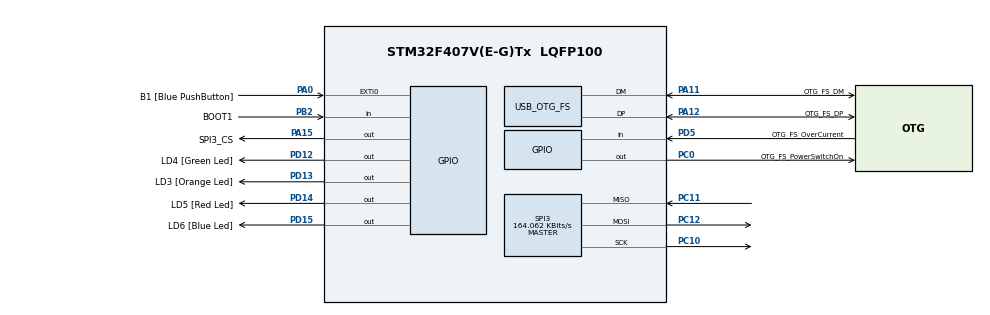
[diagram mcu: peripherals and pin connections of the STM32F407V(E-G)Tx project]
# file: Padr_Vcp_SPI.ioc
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FREERTOS.Tasks01=defaultTask,0,128,StartDefaultTask
Mcu.Family=STM32F4
Mcu.Name=STM32F407V(E-G)Tx
Mcu.Package=LQFP100
NVIC.OTG_FS_IRQn=true\:5\:0\:false
NVIC.PriorityGroup=NVIC_PRIORITYGROUP_4
PA0-WKUP.GPIO_Label=B1 [Blue PushButton]
PA0-WKUP.GPIO_ModeDefaultEXTI=GPIO_MODE_EVT_RISING
PA0-WKUP.GPIO_PuPd=GPIO_NOPULL
PA0-WKUP.Signal=GPXTI0
PA10.GPIO_Label=OTG_FS_ID
PA10.GPIO_Mode=GPIO_MODE_AF_PP
PA10.GPIO_PuPd=GPIO_NOPULL
PA10.GPIO_Speed=GPIO_SPEED_LOW
PA10.Signal=USB_OTG_FS_ID
PA11.GPIO_Label=OTG_FS_DM
PA11.GPIO_Mode=GPIO_MODE_AF_PP
PA11.GPIO_PuPd=GPIO_NOPULL
PA11.GPIO_Speed=GPIO_SPEED_LOW
PA11.Mode=Device_Only
PA11.Signal=USB_OTG_FS_DM
PA12.GPIO_Label=OTG_FS_DP
PA12.GPIO_Mode=GPIO_MODE_AF_PP
PA12.GPIO_PuPd=GPIO_NOPULL
PA12.GPIO_Speed=GPIO_SPEED_LOW
PA12.Mode=Device_Only
PA12.Signal=USB_OTG_FS_DP
PA13.GPIO_Label=SWDIO
PA13.Mode=Trace-Asynchronous_SW
PA13.Signal=SYS_JTMS-SWDIO
PA14.GPIO_Label=SWCLK
PA14.Mode=Trace-Asynchronous_SW
PA14.Signal=SYS_JTCK-SWCLK
PA15.GPIO_Label=SPI3_CS
PA15.Signal=GPIO_Output
PA9.GPIO_Label=VBUS_FS
PA9.GPIO_Mode=GPIO_MODE_INPUT
PA9.GPIO_PuPd=GPIO_NOPULL
PA9.Signal=USB_OTG_FS_VBUS
PB2.GPIO_Label=BOOT1
PB2.GPIO_Mode=GPIO_MODE_INPUT
PB2.GPIO_PuPd=GPIO_NOPULL
PB2.Signal=GPIO_Input
PB3.GPIO_Label=SWO
PB3.Mode=Trace-Asynchronous_SW
PB3.Signal=SYS_JTDO-SWO
PC0.GPIO_Label=OTG_FS_PowerSwitchOn
PC0.GPIO_PuPd=GPIO_NOPULL
PC0.GPIO_Speed=GPIO_SPEED_LOW
PC0.Signal=GPIO_Output
PC10.GPIO_Speed=GPIO_SPEED_LOW
PC10.Mode=Full_Duplex_Master
PC10.Signal=SPI3_SCK
PC11.GPIO_Speed=GPIO_SPEED_LOW
PC11.Mode=Full_Duplex_Master
PC11.Signal=SPI3_MISO
PC12.GPIO_Speed=GPIO_SPEED_LOW
PC12.Mode=Full_Duplex_Master
PC12.Signal=SPI3_MOSI
PD12.GPIO_Label=LD4 [Green Led]
PD12.GPIO_PuPd=GPIO_NOPULL
PD12.GPIO_Speed=GPIO_SPEED_LOW
PD12.Signal=GPIO_Output
PD13.GPIO_Label=LD3 [Orange Led]
PD13.GPIO_PuPd=GPIO_NOPULL
PD13.GPIO_Speed=GPIO_SPEED_LOW
PD13.Signal=GPIO_Output
PD14.GPIO_Label=LD5 [Red Led]
PD14.GPIO_PuPd=GPIO_NOPULL
PD14.GPIO_Speed=GPIO_SPEED_LOW
PD14.Signal=GPIO_Output
PD15.GPIO_Label=LD6 [Blue Led]
PD15.GPIO_PuPd=GPIO_NOPULL
PD15.GPIO_Speed=GPIO_SPEED_LOW
PD15.Signal=GPIO_Output
PD5.GPIO_Label=OTG_FS_OverCurrent
PD5.GPIO_Mode=GPIO_MODE_INPUT
PD5.GPIO_PuPd=GPIO_NOPULL
PD5.Signal=GPIO_Input
PH0-OSC_IN.GPIO_Label=PH0-OSC_IN
PH0-OSC_IN.Mode=HSE-External-Oscillator
PH0-OSC_IN.Signal=RCC_OSC_IN
PH1-OSC_OUT.GPIO_Label=PH1-OSC_OUT
PH1-OSC_OUT.Mode=HSE-External-Oscillator
PH1-OSC_OUT.Signal=RCC_OSC_OUT
ProjectManager.TargetToolchain=SW4STM32
RCC.AHBFreq_Value=168000000
RCC.APB1CLKDivider=RCC_HCLK_DIV4
RCC.APB1Freq_Value=42000000
RCC.APB1TimFreq_Value=84000000
RCC.APB2CLKDivider=RCC_HCLK_DIV2
RCC.APB2Freq_Value=84000000
RCC.APB2TimFreq_Value=168000000
RCC.CortexFreq_Value=168000000
RCC.HCLKFreq_Value=168000000
RCC.HSE_VALUE=8000000
RCC.HSI_VALUE=16000000
RCC.LSE_VALUE=32768
RCC.PLLM=8
RCC.PLLN=336
RCC.PLLQ=7
RCC.SYSCLKFreq_VALUE=168000000
RCC.SYSCLKSource=RCC_SYSCLKSOURCE_PLLCLK
RCC.VCOOutputFreq_Value=336000000
SPI3.BaudRatePrescaler=SPI_BAUDRATEPRESCALER_256
SPI3.CalculateBaudRate=164.062 KBits/s
SPI3.Mode=SPI_MODE_MASTER
USB_DEVICE.CLASS_NAME-CDC_FS=CDC
USB_DEVICE.USBD_HandleTypeDef-CDC_FS=hUsbDeviceFS
USB_DEVICE.USBD_SELF_POWERED-CDC_FS=0
USB_DEVICE.VirtualMode-CDC_FS=Cdc
USB_DEVICE.VirtualModeFS=Cdc_FS
USB_OTG_FS.VirtualMode=Device_Only
USB_OTG_FS.vbus_sensing_enable=DISABLE
VP_FREERTOS_VS_ENABLE.Mode=Enabled
VP_USB_DEVICE_VS_USB_DEVICE_CDC_FS.Mode=CDC_FS
board=STM32F4DISCOVERY

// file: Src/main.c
/**
  ******************************************************************************
  * File Name          : main.c
  * Description        : Main program body
  ******************************************************************************
  *
  * COPYRIGHT(c) 2015 STMicroelectronics
  *
  * Redistribution and use in source and binary forms, with or without modification,
  * are permitted provided that the following conditions are met:
  *   1. Redistributions of source code must retain the above copyright notice,
  *      this list of conditions and the following disclaimer.
  *   2. Redistributions in binary form must reproduce the above copyright notice,
  *      this list of conditions and the following disclaimer in the documentation
  *      and/or other materials provided with the distribution.
  *   3. Neither the name of STMicroelectronics nor the names of its contributors
  *      may be used to endorse or promote products derived from this software
  *      without specific prior written permission.
  *
  * THIS SOFTWARE IS PROVIDED BY THE COPYRIGHT HOLDERS AND CONTRIBUTORS "AS IS"
  * AND ANY EXPRESS OR IMPLIED WARRANTIES, INCLUDING, BUT NOT LIMITED TO, THE
  * IMPLIED WARRANTIES OF MERCHANTABILITY AND FITNESS FOR A PARTICULAR PURPOSE ARE
  * DISCLAIMED. IN NO EVENT SHALL THE COPYRIGHT HOLDER OR CONTRIBUTORS BE LIABLE
  * FOR ANY DIRECT, INDIRECT, INCIDENTAL, SPECIAL, EXEMPLARY, OR CONSEQUENTIAL
  * DAMAGES (INCLUDING, BUT NOT LIMITED TO, PROCUREMENT OF SUBSTITUTE GOODS OR
  * SERVICES; LOSS OF USE, DATA, OR PROFITS; OR BUSINESS INTERRUPTION) HOWEVER
  * CAUSED AND ON ANY THEORY OF LIABILITY, WHETHER IN CONTRACT, STRICT LIABILITY,
  * OR TORT (INCLUDING NEGLIGENCE OR OTHERWISE) ARISING IN ANY WAY OUT OF THE USE
  * OF THIS SOFTWARE, EVEN IF ADVISED OF THE POSSIBILITY OF SUCH DAMAGE.
  *
  ******************************************************************************
  */
#include "stm32f4xx_hal.h"
#include "cmsis_os.h"
#include "spi.h"
#include "usb_device.h"
#include "gpio.h"

/* USER CODE BEGIN PV */
/* Private variables ---------------------------------------------------------*/

/* USER CODE END PV */

void SystemClock_Config(void);
void MX_FREERTOS_Init(void);

/* USER CODE BEGIN PFP */
/* Private function prototypes -----------------------------------------------*/

/* USER CODE END PFP */

int main(void)
{

  /* MCU Configuration----------------------------------------------------------*/

  /* Reset of all peripherals, Initializes the Flash interface and the Systick. */
  HAL_Init();

  /* Configure the system clock */
  SystemClock_Config();

  /* Initialize all configured peripherals */
  MX_GPIO_Init();
  MX_SPI3_Init();

  /* USER CODE BEGIN 2 */

//  while (1)
//  {
//	  uint8_t result = CDC_Transmit_FS( array, 10);
//	  /* Insert 100 ms delay */
//	  HAL_Delay(1000);
//  }

  /* USER CODE END 2 */

  /* Call init function for freertos objects (in freertos.c) */
  MX_FREERTOS_Init();

  /* Start scheduler */
  osKernelStart();

  /* We should never get here as control is now taken by the scheduler */

  /* Infinite loop */
  while (1)
  {

  }

}

/** System Clock Configuration
*/
void SystemClock_Config(void)
{

  RCC_OscInitTypeDef RCC_OscInitStruct;
  RCC_ClkInitTypeDef RCC_ClkInitStruct;

  __PWR_CLK_ENABLE();

  __HAL_PWR_VOLTAGESCALING_CONFIG(PWR_REGULATOR_VOLTAGE_SCALE1);

  RCC_OscInitStruct.OscillatorType = RCC_OSCILLATORTYPE_HSE;
  RCC_OscInitStruct.HSEState = RCC_HSE_ON;
  RCC_OscInitStruct.PLL.PLLState = RCC_PLL_ON;
  RCC_OscInitStruct.PLL.PLLSource = RCC_PLLSOURCE_HSE;
  RCC_OscInitStruct.PLL.PLLM = 8;
  RCC_OscInitStruct.PLL.PLLN = 336;
  RCC_OscInitStruct.PLL.PLLP = RCC_PLLP_DIV2;
  RCC_OscInitStruct.PLL.PLLQ = 7;
  HAL_RCC_OscConfig(&RCC_OscInitStruct);

  RCC_ClkInitStruct.ClockType = RCC_CLOCKTYPE_SYSCLK|RCC_CLOCKTYPE_PCLK1
                              |RCC_CLOCKTYPE_PCLK2;
  RCC_ClkInitStruct.SYSCLKSource = RCC_SYSCLKSOURCE_PLLCLK;
  RCC_ClkInitStruct.AHBCLKDivider = RCC_SYSCLK_DIV1;
  RCC_ClkInitStruct.APB1CLKDivider = RCC_HCLK_DIV8;
  RCC_ClkInitStruct.APB2CLKDivider = RCC_HCLK_DIV2;
  HAL_RCC_ClockConfig(&RCC_ClkInitStruct, FLASH_LATENCY_5);

  HAL_SYSTICK_Config(HAL_RCC_GetHCLKFreq()/1000);

  HAL_SYSTICK_CLKSourceConfig(SYSTICK_CLKSOURCE_HCLK);

  /* SysTick_IRQn interrupt configuration */
  HAL_NVIC_SetPriority(SysTick_IRQn, 0, 0);
}

/************************ (C) COPYRIGHT STMicroelectronics *****END OF FILE****/

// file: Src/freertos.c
/**
  ******************************************************************************
  * File Name          : freertos.c
  * Description        : Code for freertos applications
  ******************************************************************************
  *
  * COPYRIGHT(c) 2015 STMicroelectronics
  *
  * Redistribution and use in source and binary forms, with or without modification,
  * are permitted provided that the following conditions are met:
  *   1. Redistributions of source code must retain the above copyright notice,
  *      this list of conditions and the following disclaimer.
  *   2. Redistributions in binary form must reproduce the above copyright notice,
  *      this list of conditions and the following disclaimer in the documentation
  *      and/or other materials provided with the distribution.
  *   3. Neither the name of STMicroelectronics nor the names of its contributors
  *      may be used to endorse or promote products derived from this software
  *      without specific prior written permission.
  *
  * THIS SOFTWARE IS PROVIDED BY THE COPYRIGHT HOLDERS AND CONTRIBUTORS "AS IS"
  * AND ANY EXPRESS OR IMPLIED WARRANTIES, INCLUDING, BUT NOT LIMITED TO, THE
  * IMPLIED WARRANTIES OF MERCHANTABILITY AND FITNESS FOR A PARTICULAR PURPOSE ARE
  * DISCLAIMED. IN NO EVENT SHALL THE COPYRIGHT HOLDER OR CONTRIBUTORS BE LIABLE
  * FOR ANY DIRECT, INDIRECT, INCIDENTAL, SPECIAL, EXEMPLARY, OR CONSEQUENTIAL
  * DAMAGES (INCLUDING, BUT NOT LIMITED TO, PROCUREMENT OF SUBSTITUTE GOODS OR
  * SERVICES; LOSS OF USE, DATA, OR PROFITS; OR BUSINESS INTERRUPTION) HOWEVER
  * CAUSED AND ON ANY THEORY OF LIABILITY, WHETHER IN CONTRACT, STRICT LIABILITY,
  * OR TORT (INCLUDING NEGLIGENCE OR OTHERWISE) ARISING IN ANY WAY OUT OF THE USE
  * OF THIS SOFTWARE, EVEN IF ADVISED OF THE POSSIBILITY OF SUCH DAMAGE.
  *
  ******************************************************************************
  */

#include "stdlib.h"
#include "FreeRTOS.h"
#include "task.h"
#include "cmsis_os.h"
#include "usbd_cdc_if.h"
#include "lcd.h"
#include "spi.h"
#include "stm32f4_discovery.h"

/* USER CODE BEGIN Includes */
/* Buffer used for transmission */
uint8_t aTxBufferY[] = {0x90, 0, 0};
uint8_t aTxBufferX[] = {0xD0, 0, 0};

uint8_t aRxBufferY[] = {0, 0, 0};
uint8_t aRxBufferX[] = {0, 0, 0};

uint16_t X_pos_ = 0;
uint16_t Y_pos_ = 0;

uint16_t x1 = 0;
uint16_t x2 = 0;

//uint16_t y1 = 0;
//uint16_t y2 = 0;

/* Buffer used for reception */
//uint8_t aRxBuffer[BUFFERSIZE];
/* USER CODE END 0 */

#define	CMD_RDX 	0x94 // 12 bit conv, sigle-ended, Y-measure
#define	CMD_RDY 	0xD4 // 12 bit conv, sigle-ended, X-measure
/* USER CODE END Includes */

osThreadId defaultTaskHandle;

/* USER CODE BEGIN Variables */
extern SPI_HandleTypeDef hspi3;
/* USER CODE END Variables */

void StartDefaultTask(void const * argument);

extern void MX_USB_DEVICE_Init(void);
void MX_FREERTOS_Init(void); /* (MISRA C 2004 rule 8.1) */

/* Hook prototypes */

/* Init FreeRTOS */

void MX_FREERTOS_Init(void) {

  /* Create the thread(s) */
  /* definition and creation of defaultTask */
  osThreadDef(defaultTask, StartDefaultTask, osPriorityNormal, 0, 128);
  defaultTaskHandle = osThreadCreate(osThread(defaultTask), NULL);

}

/* StartDefaultTask function */
void StartDefaultTask(void const * argument)
{
  /* init code for USB_DEVICE */
  MX_USB_DEVICE_Init();

  /* USER CODE BEGIN StartDefaultTask */
  /* Infinite loop */
  uint8_t Xarray[] = "X = ";
  uint8_t Yarray[] = " Y = ";
  uint8_t NewLine[] = "\r\n";
  uint16_t sizeOf_Xarray = sizeof(Xarray)/sizeof(Xarray[0]) - 1;
  uint16_t sizeOf_Yarray = sizeof(Yarray)/sizeof(Yarray[0]) - 1;
  uint16_t sizeOf_NewLine = sizeof(NewLine)/sizeof(NewLine[0]) - 1;

  uint8_t Xstring[] = "       ";
  uint8_t Ystring[] = "       ";
  uint16_t sizeOf_string = sizeof(Ystring)/sizeof(Ystring[0]) - 1;
  HAL_Delay(1000);

  ClrP( SPI3_CS );

  float X_resolution = (float)3780 / 640;
  float Y_resolution = (float)3600 / 480;

  uint32_t X_640_old = 0;
  uint32_t Y_480_old = 0;

  for(;;)
  {
	BSP_LED_Toggle(LED4);
    osDelay(10);

    HAL_SPI_TransmitReceive(&hspi3,(uint8_t*)aTxBufferY, (uint8_t *)aRxBufferY, 3, 500);
    HAL_SPI_TransmitReceive(&hspi3,(uint8_t*)aTxBufferX, (uint8_t *)aRxBufferX, 3, 500);
    uint32_t *Y_temp = (uint32_t*)(aRxBufferX);
    uint32_t *X_temp = (uint32_t*)(aRxBufferY);

    uint32_t Y_temp1 = *Y_temp;
    uint32_t X_temp1 = *X_temp;

    X_temp1 >>= 8;
    uint32_t X_temp1_rev_first7_bits = 0x7F & X_temp1;
    X_temp1 >>= 11;
    X_temp1 = X_temp1 | (X_temp1_rev_first7_bits<<5);

    Y_temp1 >>= 8;
    uint32_t Y_temp1_rev_first7_bits = 0x7F & Y_temp1;
    Y_temp1 >>= 11;
    Y_temp1 = Y_temp1 | (Y_temp1_rev_first7_bits<<5);

    if( Y_temp1 != 0x000 )
    {
        if( 3900 < X_temp1) { X_temp1 = 3900; }
        if( (120 > X_temp1) && (0 != X_temp1) ) { X_temp1 = 120; }

        if( 3800 < Y_temp1) { Y_temp1 = 3800; }
        if( (200 > Y_temp1) && (0 != Y_temp1) ) { Y_temp1 = 200; }

        X_temp1 = X_temp1 - 3900;
        X_temp1 = abs(X_temp1);

        uint32_t X_640 = X_temp1/X_resolution;
        uint32_t Y_480 = (Y_temp1 - 200)/Y_resolution;

    	if( (X_640 != X_640_old) || (Y_480 != Y_480_old) )
    	{
    		itoa(X_640, (char*)Xstring, 10);
    		itoa(Y_480, (char*)Ystring, 10);

            CDC_Transmit_FS( Xarray,  sizeOf_Xarray );
            HAL_Delay(1);
            CDC_Transmit_FS( Xstring,  sizeOf_string );
            HAL_Delay(1);
            CDC_Transmit_FS( Yarray,  sizeOf_Yarray );
            HAL_Delay(1);
            CDC_Transmit_FS( Ystring,  sizeOf_string );
            HAL_Delay(1);
            CDC_Transmit_FS( NewLine, sizeOf_NewLine );
            HAL_Delay(10);
            BSP_LED_Toggle(LED5);
            X_640_old = X_640;
            Y_480_old = Y_480;
    	}
    }

    // clearing
    uint16_t i = 0;
    for(i = 0; i < 3; ++i )
    {
    	aRxBufferY[i] = 0;
    	aRxBufferX[i] = 0;
    }

    for( i=0; i<sizeOf_string; ++i)
    {
    	Xstring[i] = ' ';
    	Ystring[i] = ' ';
    }

  }
  /* USER CODE END StartDefaultTask */
}

/************************ (C) COPYRIGHT STMicroelectronics *****END OF FILE****/
